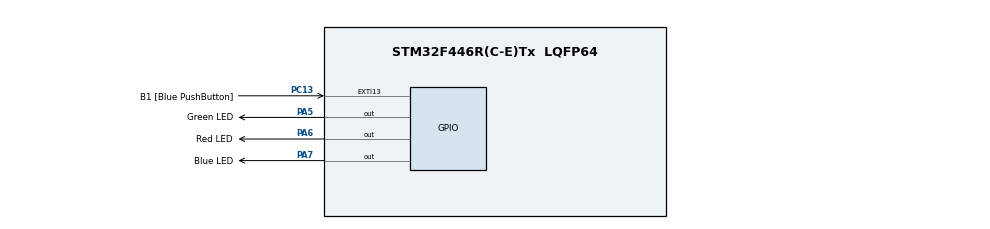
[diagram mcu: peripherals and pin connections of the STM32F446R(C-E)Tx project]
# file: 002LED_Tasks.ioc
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Mcu.Family=STM32F4
Mcu.Name=STM32F446R(C-E)Tx
Mcu.Package=LQFP64
NVIC.PriorityGroup=NVIC_PRIORITYGROUP_4
NVIC.TIM6_DAC_IRQn=true\:0\:0\:false\:false\:true\:false\:true\:true
NVIC.TimeBase=TIM6_DAC_IRQn
NVIC.TimeBaseIP=TIM6
PA13.GPIO_Label=TMS
PA13.Signal=SYS_JTMS-SWDIO
PA14.GPIO_Label=TCK
PA14.Signal=SYS_JTCK-SWCLK
PA2.GPIO_Label=USART_TX
PA2.Signal=USART2_TX
PA3.GPIO_Label=USART_RX
PA3.Signal=USART2_RX
PA5.GPIO_Label=Green LED
PA5.Signal=GPIO_Output
PA6.GPIO_Label=Red LED
PA6.Signal=GPIO_Output
PA7.GPIO_Label=Blue LED
PA7.Signal=GPIO_Output
PB3.GPIO_Label=SWO
PB3.Signal=SYS_JTDO-SWO
PC13.GPIO_Label=B1 [Blue PushButton]
PC13.GPIO_ModeDefaultEXTI=GPIO_MODE_IT_FALLING
PC13.Signal=GPXTI13
PC14-OSC32_IN.Signal=RCC_OSC32_IN
PC15-OSC32_OUT.Signal=RCC_OSC32_OUT
PH0-OSC_IN.Signal=RCC_OSC_IN
PH1-OSC_OUT.Signal=RCC_OSC_OUT
ProjectManager.HeapSize=0x200
ProjectManager.StackSize=0x400
ProjectManager.TargetToolchain=STM32CubeIDE
RCC.AHBFreq_Value=84000000
RCC.APB1CLKDivider=RCC_HCLK_DIV2
RCC.APB1Freq_Value=21000000
RCC.APB1TimFreq_Value=42000000
RCC.APB2Freq_Value=42000000
RCC.APB2TimFreq_Value=42000000
RCC.CortexFreq_Value=84000000
RCC.FLatency-AdvancedSettings=FLASH_LATENCY_2
RCC.HCLKFreq_Value=84000000
RCC.HSE_VALUE=8000000
RCC.HSI_VALUE=16000000
RCC.LSE_VALUE=32768
RCC.PLLN=168
RCC.PLLP=RCC_PLLP_DIV4
RCC.SYSCLKFreq_VALUE=42000000
RCC.SYSCLKSource=RCC_SYSCLKSOURCE_PLLCLK
RCC.USBFreq_Value=168000000
RCC.VCOOutputFreq_Value=168000000
VP_SYS_VS_tim6.Mode=TIM6
board=NUCLEO-F446RE

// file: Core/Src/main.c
/* USER CODE BEGIN Header */
/**
  ******************************************************************************
  * @file           : main.c
  * @brief          : Main program body
  ******************************************************************************
  * @attention
  *
  * Copyright (c) 2022 STMicroelectronics.
  * All rights reserved.
  *
  * This software is licensed under terms that can be found in the LICENSE file
  * in the root directory of this software component.
  * If no LICENSE file comes with this software, it is provided AS-IS.
  *
  ******************************************************************************
  */
/* USER CODE END Header */
#include "main.h"

/* USER CODE BEGIN Includes */
#include "stdio.h"
#include "FreeRTOS.h"
#include "task.h"
/* USER CODE END Includes */

/* USER CODE BEGIN PV */
#define DWT_CTRL 				(*(volatile uint32_t*)0xE0001000)
/* USER CODE END PV */

void SystemClock_Config(void);
static void MX_GPIO_Init(void);
/* USER CODE BEGIN PFP */
extern  void SEGGER_UART_init(uint32_t);
/* USER CODE END PFP */

/* USER CODE BEGIN 0 */
static void led_green_handler(void* param);
static void led_red_handler(void* param);
static void led_blue_handler(void* param);
/* USER CODE END 0 */

int main(void)
{

  /* MCU Configuration--------------------------------------------------------*/

  /* Reset of all peripherals, Initializes the Flash interface and the Systick. */
  HAL_Init();

  /* Configure the system clock */
  SystemClock_Config();

  /* Initialize all configured peripherals */
  MX_GPIO_Init();
  /* USER CODE BEGIN 2 */
  BaseType_t status;

  TaskHandle_t task1_handle;
  TaskHandle_t task2_handle;
  TaskHandle_t task3_handle;

  // Enable the CYCCNT counter
  DWT_CTRL |= (1 << 0);

  SEGGER_UART_init(500000);
  SEGGER_SYSVIEW_Conf();

  status = xTaskCreate(led_green_handler,"LED_green_task",200,NULL,2,&task1_handle);
  configASSERT(status == pdPASS);

  status = xTaskCreate(led_red_handler,"LED_red_task",200,NULL,2,&task2_handle);
  configASSERT(status == pdPASS);

  status = xTaskCreate(led_blue_handler,"LED_blue_task",200,NULL,2,&task3_handle);
  configASSERT(status == pdPASS);

  // Start the real time scheduler
    vTaskStartScheduler();

  /* USER CODE END 2 */

  /* Infinite loop */
  while (1)
  {

  }
}

void SystemClock_Config(void)
{
  RCC_OscInitTypeDef RCC_OscInitStruct = {0};
  RCC_ClkInitTypeDef RCC_ClkInitStruct = {0};

  /** Configure the main internal regulator output voltage
  */
  __HAL_RCC_PWR_CLK_ENABLE();
  __HAL_PWR_VOLTAGESCALING_CONFIG(PWR_REGULATOR_VOLTAGE_SCALE3);

  /** Initializes the RCC Oscillators according to the specified parameters
  * in the RCC_OscInitTypeDef structure.
  */
  RCC_OscInitStruct.OscillatorType = RCC_OSCILLATORTYPE_HSI;
  RCC_OscInitStruct.HSIState = RCC_HSI_ON;
  RCC_OscInitStruct.HSICalibrationValue = RCC_HSICALIBRATION_DEFAULT;
  RCC_OscInitStruct.PLL.PLLState = RCC_PLL_ON;
  RCC_OscInitStruct.PLL.PLLSource = RCC_PLLSOURCE_HSI;
  RCC_OscInitStruct.PLL.PLLM = 16;
  RCC_OscInitStruct.PLL.PLLN = 336;
  RCC_OscInitStruct.PLL.PLLP = RCC_PLLP_DIV4;
  RCC_OscInitStruct.PLL.PLLQ = 2;
  RCC_OscInitStruct.PLL.PLLR = 2;
  if (HAL_RCC_OscConfig(&RCC_OscInitStruct) != HAL_OK)
  {
    Error_Handler();
  }

  /** Initializes the CPU, AHB and APB buses clocks
  */
  RCC_ClkInitStruct.ClockType = RCC_CLOCKTYPE_HCLK|RCC_CLOCKTYPE_SYSCLK
                              |RCC_CLOCKTYPE_PCLK1|RCC_CLOCKTYPE_PCLK2;
  RCC_ClkInitStruct.SYSCLKSource = RCC_SYSCLKSOURCE_PLLCLK;
  RCC_ClkInitStruct.AHBCLKDivider = RCC_SYSCLK_DIV1;
  RCC_ClkInitStruct.APB1CLKDivider = RCC_HCLK_DIV2;
  RCC_ClkInitStruct.APB2CLKDivider = RCC_HCLK_DIV1;

  if (HAL_RCC_ClockConfig(&RCC_ClkInitStruct, FLASH_LATENCY_2) != HAL_OK)
  {
    Error_Handler();
  }
}

static void MX_GPIO_Init(void)
{
  GPIO_InitTypeDef GPIO_InitStruct = {0};

  /* GPIO Ports Clock Enable */
  __HAL_RCC_GPIOC_CLK_ENABLE();
  __HAL_RCC_GPIOH_CLK_ENABLE();
  __HAL_RCC_GPIOA_CLK_ENABLE();
  __HAL_RCC_GPIOB_CLK_ENABLE();

  /*Configure GPIO pin Output Level */
  HAL_GPIO_WritePin(GPIOA, Green_LED_Pin|Red_LED_Pin|Blue_LED_Pin, GPIO_PIN_RESET);

  /*Configure GPIO pin : B1_Pin */
  GPIO_InitStruct.Pin = B1_Pin;
  GPIO_InitStruct.Mode = GPIO_MODE_IT_FALLING;
  GPIO_InitStruct.Pull = GPIO_NOPULL;
  HAL_GPIO_Init(B1_GPIO_Port, &GPIO_InitStruct);

  /*Configure GPIO pins : USART_TX_Pin USART_RX_Pin */
  GPIO_InitStruct.Pin = USART_TX_Pin|USART_RX_Pin;
  GPIO_InitStruct.Mode = GPIO_MODE_AF_PP;
  GPIO_InitStruct.Pull = GPIO_NOPULL;
  GPIO_InitStruct.Speed = GPIO_SPEED_FREQ_VERY_HIGH;
  GPIO_InitStruct.Alternate = GPIO_AF7_USART2;
  HAL_GPIO_Init(GPIOA, &GPIO_InitStruct);

  /*Configure GPIO pins : Green_LED_Pin Red_LED_Pin Blue_LED_Pin */
  GPIO_InitStruct.Pin = Green_LED_Pin|Red_LED_Pin|Blue_LED_Pin;
  GPIO_InitStruct.Mode = GPIO_MODE_OUTPUT_PP;
  GPIO_InitStruct.Pull = GPIO_NOPULL;
  GPIO_InitStruct.Speed = GPIO_SPEED_FREQ_LOW;
  HAL_GPIO_Init(GPIOA, &GPIO_InitStruct);

}

/* USER CODE BEGIN 4 */
static void led_green_handler(void* param){
	while(1) {
		SEGGER_SYSVIEW_PrintfTarget("Toggling green LED");
		HAL_GPIO_TogglePin(GPIOA,Green_LED_Pin);
		vTaskDelay(pdMS_TO_TICKS(1000));
	}

}
static void led_red_handler(void* param){
	while(1) {
		SEGGER_SYSVIEW_PrintfTarget("Toggling red LED");
		HAL_GPIO_TogglePin(GPIOA,Red_LED_Pin);
		vTaskDelay(pdMS_TO_TICKS(800));
	}
}
static void led_blue_handler(void* param){
	while(1) {
		SEGGER_SYSVIEW_PrintfTarget("Toggling blue LED");
		HAL_GPIO_TogglePin(GPIOA,Blue_LED_Pin);
		vTaskDelay(pdMS_TO_TICKS(400));
	}
}

/* USER CODE END 4 */

void HAL_TIM_PeriodElapsedCallback(TIM_HandleTypeDef *htim)
{
  if (htim->Instance == TIM6) {
    HAL_IncTick();
  }
}

void Error_Handler(void)
{
  __disable_irq();
  while (1)
  {
  }
}
